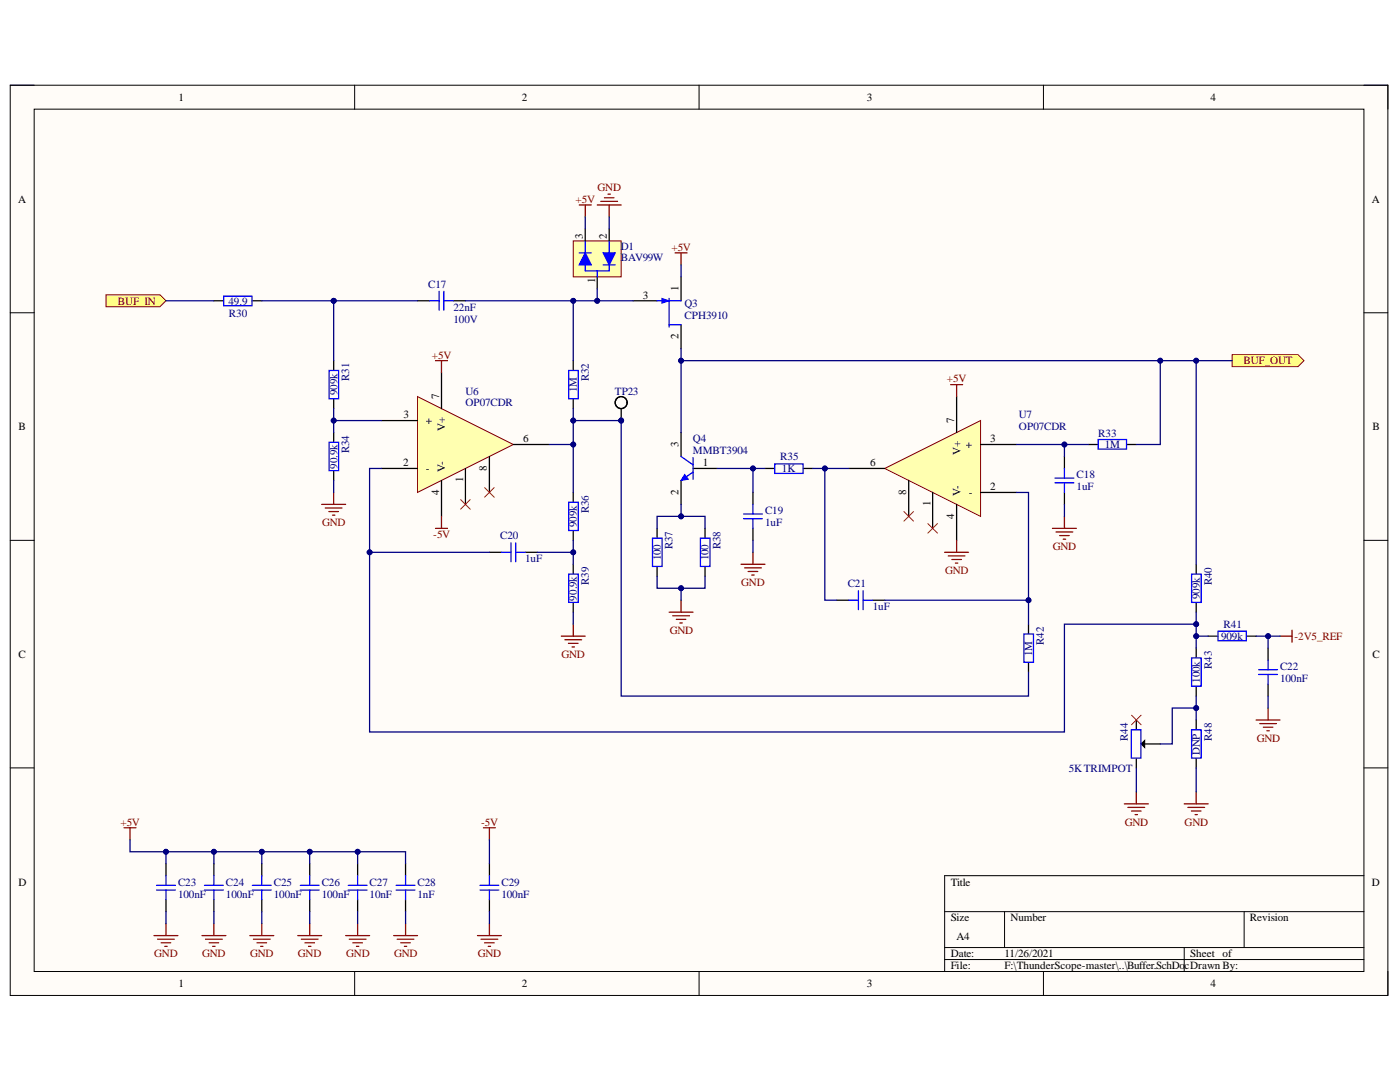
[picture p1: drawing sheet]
<svg xmlns="http://www.w3.org/2000/svg" width="279mm" height="216mm" viewBox="0 0 279 216" stroke-linecap="round" stroke-linejoin="round" font-family="sans-serif">
<defs><g id="words">
<g font-size="2.2">
<text x="35.6" y="20.1">1</text>
<text x="104.1" y="20.1">2</text>
<text x="173" y="20.1">3</text>
<text x="241.6" y="20.1">4</text>
<text x="3.6" y="40.4">A</text>
<text x="273.8" y="40.4">A</text>
<text x="116.3" y="47.6" transform="rotate(-90 116.3 47.6)">3</text>
<text x="121.1" y="47.6" transform="rotate(-90 121.1 47.6)">2</text>
<text x="118.8" y="56.5" transform="rotate(-90 118.8 56.5)">1</text>
<text x="128.3" y="59.6">3</text>
<text x="135.4" y="58.1" transform="rotate(-90 135.4 58.1)">1</text>
<text x="135.4" y="67.7" transform="rotate(-90 135.4 67.7)">2</text>
<text x="80.5" y="83.5">3</text>
<text x="87.6" y="79.6" transform="rotate(-90 87.6 79.6)">7</text>
<text x="3.7" y="85.8">B</text>
<text x="85" y="84.6">+</text>
<text x="88.8" y="85.9" transform="rotate(-90 88.8 85.9)">V+</text>
<text x="104.4" y="88.3">6</text>
<text x="135.4" y="89.1" transform="rotate(-90 135.4 89.1)">3</text>
<text x="190.4" y="84.4" transform="rotate(-90 190.4 84.4)">7</text>
<text x="192.8" y="89.5">+</text>
<text x="197.6" y="88.3">3</text>
<text x="273.9" y="85.8">B</text>
<text x="80.4" y="93">2</text>
<text x="85" y="94.2">-</text>
<text x="88.8" y="94.2" transform="rotate(-90 88.8 94.2)">V-</text>
<text x="97.2" y="94" transform="rotate(-90 97.2 94)">8</text>
<text x="140.2" y="93">1</text>
<text x="173.7" y="93">6</text>
<text x="191.7" y="90.7" transform="rotate(-90 191.7 90.7)">V+</text>
<text x="87.6" y="98.8" transform="rotate(-90 87.6 98.8)">4</text>
<text x="92.5" y="96.2" transform="rotate(-90 92.5 96.2)">1</text>
<text x="135.4" y="98.8" transform="rotate(-90 135.4 98.8)">2</text>
<text x="180.8" y="98.8" transform="rotate(-90 180.8 98.8)">8</text>
<text x="185.7" y="101" transform="rotate(-90 185.7 101)">1</text>
<text x="191.7" y="98.9" transform="rotate(-90 191.7 98.9)">V-</text>
<text x="193.4" y="99">-</text>
<text x="197.6" y="97.8">2</text>
<text x="190.4" y="103.6" transform="rotate(-90 190.4 103.6)">4</text>
<text x="3.7" y="131.3">C</text>
<text x="273.9" y="131.3">C</text>
<text x="3.7" y="176.7">D</text>
<text x="189.7" y="176.7">Title</text>
<text x="273.8" y="176.7">D</text>
<text x="189.7" y="183.8">Size</text>
<text x="201.7" y="183.8">Number</text>
<text x="249.4" y="183.8">Revision</text>
<text x="189.7" y="191">Date:</text>
<text x="190.9" y="187.5">A4</text>
<text x="200.5" y="191">11/26/2021</text>
<text x="237.5" y="191">Sheet of</text>
<text x="35.6" y="197">1</text>
<text x="104.1" y="197">2</text>
<text x="173" y="197">3</text>
<text x="189.7" y="193.4">File:</text>
<text x="200.5" y="193.4">F:\ThunderScope-master\..\Buffer.SchDo</text>
<text x="236.4" y="193.4">cDrawn By:</text>
<text x="241.6" y="197">4</text>
</g>
<g font-size="2.2" fill="#800000">
<text x="114.9" y="40.4">+5V</text>
<text x="119.3" y="38.1">GND</text>
<text x="134" y="50.1">+5V</text>
<text x="23.5" y="60.8">BUF_IN</text>
<text x="86.2" y="71.5">+5V</text>
<text x="189" y="76.3">+5V</text>
<text x="248.2" y="72.7">BUF_OUT</text>
<text x="64.3" y="105">GND</text>
<text x="86.4" y="107.4">-5V</text>
<text x="210.1" y="109.8">GND</text>
<text x="147.9" y="116.9">GND</text>
<text x="188.6" y="114.6">GND</text>
<text x="112.1" y="131.3">GND</text>
<text x="133.6" y="126.5">GND</text>
<text x="258.3" y="127.7">-2V5_REF</text>
<text x="250.8" y="148">GND</text>
<text x="24" y="164.7">+5V</text>
<text x="96" y="164.7">-5V</text>
<text x="224.5" y="164.7">GND</text>
<text x="236.4" y="164.7">GND</text>
<text x="30.8" y="191">GND</text>
<text x="40.3" y="191">GND</text>
<text x="49.9" y="191">GND</text>
<text x="59.5" y="191">GND</text>
<text x="69.1" y="191">GND</text>
<text x="78.7" y="191">GND</text>
<text x="95.3" y="191">GND</text>
</g>
<g font-size="2.2" fill="#000080">
<text x="123.9" y="49.8">D1</text>
<text x="123.9" y="52.2">BAV99W</text>
<text x="85.4" y="57.4">C17</text>
<text x="45.6" y="60.8">49.9</text>
<text x="45.7" y="63.2">R30</text>
<text x="90.5" y="64.4">100V</text>
<text x="90.5" y="62">22nF</text>
<text x="136.6" y="61.2">Q3</text>
<text x="136.6" y="63.7">CPH3910</text>
<text x="69.7" y="76" transform="rotate(-90 69.7 76)">R31</text>
<text x="117.5" y="76.1" transform="rotate(-90 117.5 76.1)">R32</text>
<text x="67.3" y="78.9" transform="rotate(-90 67.3 78.9)">909k</text>
<text x="92.9" y="78.7">U6</text>
<text x="92.9" y="81.1">OP07CDR</text>
<text x="115.1" y="78.2" transform="rotate(-90 115.1 78.2)">1M</text>
<text x="122.7" y="78.7">TP23</text>
<text x="203.3" y="83.5">U7</text>
<text x="138.3" y="88.3">Q4</text>
<text x="203.3" y="85.8">OP07CDR</text>
<text x="219.2" y="87.3">R33</text>
<text x="220.5" y="89.5">1M</text>
<text x="67.3" y="93.5" transform="rotate(-90 67.3 93.5)">90.9k</text>
<text x="69.7" y="90.5" transform="rotate(-90 69.7 90.5)">R34</text>
<text x="138.3" y="90.7">MMBT3904</text>
<text x="155.7" y="91.8">R35</text>
<text x="156.1" y="94.2">1K</text>
<text x="214.9" y="95.5">C18</text>
<text x="214.9" y="97.8">1uF</text>
<text x="99.8" y="107.6">C20</text>
<text x="115.1" y="105.2" transform="rotate(-90 115.1 105.2)">909k</text>
<text x="117.5" y="102.4" transform="rotate(-90 117.5 102.4)">R36</text>
<text x="152.7" y="102.6">C19</text>
<text x="152.7" y="105">1uF</text>
<text x="104.8" y="112.1">1uF</text>
<text x="131.9" y="111.8" transform="rotate(-90 131.9 111.8)">100</text>
<text x="134.2" y="109.6" transform="rotate(-90 134.2 109.6)">R37</text>
<text x="141.4" y="111.8" transform="rotate(-90 141.4 111.8)">100</text>
<text x="143.8" y="109.5" transform="rotate(-90 143.8 109.5)">R38</text>
<text x="115.1" y="119.8" transform="rotate(-90 115.1 119.8)">90.9k</text>
<text x="117.5" y="116.7" transform="rotate(-90 117.5 116.7)">R39</text>
<text x="169.2" y="117.2">C21</text>
<text x="239.5" y="119.6" transform="rotate(-90 239.5 119.6)">909k</text>
<text x="241.8" y="116.8" transform="rotate(-90 241.8 116.8)">R40</text>
<text x="174.2" y="121.7">1uF</text>
<text x="244.2" y="125.3">R41</text>
<text x="206" y="130.8" transform="rotate(-90 206 130.8)">1M</text>
<text x="208.3" y="128.7" transform="rotate(-90 208.3 128.7)">R42</text>
<text x="243.7" y="127.7">909k</text>
<text x="239.5" y="136.2" transform="rotate(-90 239.5 136.2)">100k</text>
<text x="241.8" y="133.4" transform="rotate(-90 241.8 133.4)">R43</text>
<text x="255.5" y="133.7">C22</text>
<text x="255.5" y="136.1">100nF</text>
<text x="225.1" y="147.8" transform="rotate(-90 225.1 147.8)">R44</text>
<text x="241.8" y="147.8" transform="rotate(-90 241.8 147.8)">R48</text>
<text x="213.3" y="154">5KTRIMPOT</text>
<text x="239.5" y="150.6" transform="rotate(-90 239.5 150.6)">DNP</text>
<text x="35.5" y="176.7">C23</text>
<text x="35.5" y="179.1">100nF</text>
<text x="45.1" y="176.7">C24</text>
<text x="45.1" y="179.1">100nF</text>
<text x="54.6" y="176.7">C25</text>
<text x="54.6" y="179.1">100nF</text>
<text x="64.2" y="176.7">C26</text>
<text x="64.2" y="179.1">100nF</text>
<text x="73.8" y="176.7">C27</text>
<text x="73.8" y="179.1">10nF</text>
<text x="83.3" y="176.7">C28</text>
<text x="83.3" y="179.1">1nF</text>
<text x="100.1" y="176.7">C29</text>
<text x="100.1" y="179.1">100nF</text>
</g>
</g></defs>
<path d="M2 17h275v181.6h-275z" fill-rule="evenodd" fill="#fffcf8"/>
<path d="M2 17h275v181.6h-275z" fill="none" stroke="#000" stroke-width=".2"/>
<path d="M6.8 21.8h265.4v172.1h-265.4z" fill-rule="evenodd" fill="#fffcf8"/>
<g fill="none" stroke="#000" stroke-width=".2">
<path d="M2 17h4.8M70.8 17v4.8M139.5 17v4.8M208.2 17v4.8M272.2 17h4.8v4.8M6.8 21.8h265.4v172.1h-265.4zM2 62.4h4.8M272.2 62.4h4.8M2 107.8h4.8M272.2 107.8h4.8M2 153.2h4.8M272.2 153.2h4.8"/>
<path d="M272.2 174.7h-83.7v19.2M70.8 193.9v4.7M139.5 193.9v4.7M188.5 181.9h83.7M188.5 189.1h83.7M188.5 191.5h83.7M200.5 181.9v7.2M208.2 193.9v4.7M236.3 189.1v4.8M248.3 181.9v7.2M277 193.9v4.7"/>
</g>
<path d="M66.6 98.3v2.3M64.2 100.6h4.8M64.9 101.4h3.4M65.6 102.1h1.9M66.4 102.8h.4" fill="none" stroke="#800000" stroke-width=".25"/>
<path d="M83.3 79.1l19.2 9.6-19.2 9.6z" fill="#ffffb0"/>
<path d="M83.3 79.1l19.2 9.6-19.2 9.6z" fill="none" stroke="#800000" stroke-width=".2"/>
<path d="M88.1 74.4v7.1M76.2 83.9h7.1M76.2 93.5h7.1M88.1 95.9v7.1M92.9 93.5v7.1M97.7 91.1v7.2M102.5 88.7h7.1" fill="none" stroke="#000" stroke-width=".25"/>
<path d="M86.9 72h2.4M88.1 72v2.4M86.9 105.4h2.4M88.1 103v2.4M112 126.9h4.8M112.7 127.7h3.4M113.4 128.4h2M114.2 129.1h.4M114.4 124.5v2.4" fill="none" stroke="#800000" stroke-width=".25"/>
<path d="M91.9 99.7l1.9 1.9M93.8 99.7l-1.9 1.9M96.7 97.3l1.9 1.9M98.6 97.3l-1.9 1.9" fill="none" stroke="#f00" stroke-width=".2"/>
<path d="M21.2 58.8h10.7l1.2 1.2-1.2 1.2h-10.7z" fill-rule="evenodd" fill="#ffff80"/>
<path d="M21.2 58.8h10.7l1.2 1.2-1.2 1.2h-10.7z" fill="none" stroke="#800000" stroke-width=".2"/>
<path d="M114.4 72v1.8M114.4 79.6v1.9M135.9 86.3v4.8M135.9 95.9v4.7M138.3 93.5h4.8M97.7 110.2h2.4M104.8 110.2h2.4" fill="none" stroke="#000" stroke-width=".25"/>
<path d="M113.5 73.9h1.9v5.7h-1.9zM135.9 91.1l2.4 1.7M138.3 94.2l-2.4 1.7M138.3 91.3v4.3M100.1 110.2h1.9M102 108.3v3.8M102.9 110.2h1.9M102.9 108.3v3.8" fill="none" stroke="#00f" stroke-width=".25"/>
<path d="M134.7 50.5h2.4M135.9 50.5v2.4" fill="none" stroke="#800000" stroke-width=".25"/>
<path d="M136.6 94.7l.8 .9-1.5 .3z" fill="#00f"/>
<path d="M136.6 94.7l.8 .9-1.5 .3z" fill="none" stroke="#00f" stroke-width=".2"/>
<path d="M131.1 105.4v1.9M131.1 113.1v1.9M140.7 105.4v1.9M140.7 113.1v1.9" fill="none" stroke="#000" stroke-width=".25"/>
<path d="M130.2 107.4h1.9v5.6h-1.9zM139.8 107.4h1.9v5.6h-1.9z" fill="none" stroke="#00f" stroke-width=".25"/>
<path d="M135.9 119.8v2.4M133.5 122.2h4.8M134.2 122.9h3.4M135 123.6h1.9M135.7 124.3h.5" fill="none" stroke="#800000" stroke-width=".25"/>
<path d="M176.6 93.5l19.1-9.6v19.1z" fill="#ffffb0"/>
<path d="M176.6 93.5l19.1-9.6v19.1z" fill="none" stroke="#800000" stroke-width=".2"/>
<path d="M190.9 79.1v7.2M169.4 93.5h7.2M181.4 95.9v7.1M186.1 98.3v7.1M195.7 88.7h7.2M195.7 98.3h7.2M217.2 88.7h1.9M224.9 88.7h1.9M190.9 100.7v7.1M205.3 124.5v1.9M205.3 132.2v1.9" fill="none" stroke="#000" stroke-width=".25"/>
<path d="M189.7 76.8h2.4M190.9 76.8v2.3M147.9 112.6h4.8M148.6 113.3h3.3M149.3 114h1.9M150 114.7h.5M150.3 110.2v2.4M210 105.4h4.8M210.8 106.1h3.3M211.5 106.9h1.9M212.2 107.6h.5M212.4 103v2.4" fill="none" stroke="#800000" stroke-width=".25"/>
<path d="M180.4 102.1l1.9 1.9M182.3 102.1l-1.9 1.9M185.2 104.5l1.9 1.9M187.1 104.5l-1.9 1.9" fill="none" stroke="#f00" stroke-width=".2"/>
<path d="M219.2 87.7h5.6v1.9h-5.6zM204.3 126.5h2v5.6h-2z" fill="none" stroke="#00f" stroke-width=".25"/>
<path d="M245.9 70.8h13.1l1.2 1.2-1.2 1.2h-13.1z" fill-rule="evenodd" fill="#ffff80"/>
<path d="M245.9 70.8h13.1l1.2 1.2-1.2 1.2h-13.1z" fill="none" stroke="#800000" stroke-width=".2"/>
<g fill="none" stroke="#000" stroke-width=".25">
<path d="M135.9 55.2v4.8M126.4 60h4.7M135.9 64.8v4.8M212.4 91.1v2.4M212.4 98.3v2.4M167 119.8h2.4M174.2 119.8h2.4M42.7 172.3v2.4M42.7 179.5v2.4M52.2 172.3v2.4M52.2 179.5v2.4M61.8 172.3v2.4"/>
<path d="M61.8 179.5v2.4M71.4 172.3v2.4M71.4 179.5v2.4M80.9 172.3v2.4M80.9 179.5v2.4M97.7 172.3v2.4M97.7 179.5v2.4"/>
</g>
<g fill="none" stroke="#00f" stroke-width=".25">
<path d="M133.5 59.5v5.8M131.1 60h2.4M210.5 96.3h3.8M210.5 95.4h3.8M212.4 93.5v1.9M212.4 96.3v2M169.4 119.8h1.9M171.3 117.9v3.7M172.3 117.9v3.7M172.3 119.8h1.9M40.8 176.7h3.8M40.8 177.6h3.8"/>
<path d="M42.7 174.7v2M42.7 177.6v1.9M50.4 176.7h3.7M50.4 177.6h3.7M52.2 174.7v2M52.2 177.6v1.9M59.9 176.7h3.8M59.9 177.6h3.8M61.8 174.7v2M61.8 177.6v1.9M69.5 176.7h3.8M69.5 177.6h3.8"/>
<path d="M71.4 174.7v2M71.4 177.6v1.9M79.1 176.7h3.7M79.1 177.6h3.7M80.9 174.7v2M80.9 177.6v1.9M95.8 176.7h3.8M95.8 177.6h3.8M97.7 174.7v2M97.7 177.6v1.9"/>
</g>
<g fill="none" stroke="#800000" stroke-width=".25">
<path d="M188.5 110.2h4.8M189.2 110.9h3.4M190 111.6h1.9M190.7 112.4h.5M190.9 107.8v2.4M24.8 165.2h2.3M25.9 165.2v2.4M96.5 165.2h2.4M97.7 165.2v2.4M40.3 186.7h4.8M41 187.4h3.4M41.7 188.1h1.9"/>
<path d="M42.4 188.8h.5M42.7 184.3v2.4M49.9 186.7h4.7M50.6 187.4h3.3M51.3 188.1h1.9M52 188.8h.5M52.2 184.3v2.4M59.4 186.7h4.8M60.1 187.4h3.4M60.8 188.1h2M61.6 188.8h.5M61.8 184.3v2.4"/>
<path d="M69 186.7h4.8M69.7 187.4h3.4M70.4 188.1h1.9M71.1 188.8h.5M71.4 184.3v2.4M78.5 186.7h4.8M79.3 187.4h3.3M80 188.1h1.9M80.7 188.8h.5M80.9 184.3v2.4M95.3 186.7h4.8M96 187.4h3.3"/>
<path d="M96.7 188.1h1.9M97.4 188.8h.5M97.7 184.3v2.4"/>
</g>
<path d="M132.1 59.5l1.4 .5-1.4 .5z" fill="#00f"/>
<path d="M132.1 59.5l1.4 .5-1.4 .5z" fill="none" stroke="#00f" stroke-width=".2"/>
<g fill="none" stroke="#00f" stroke-width=".25">
<path d="M87.6 58.1v3.8M88.6 58.1v3.8M65.7 73.9h1.9v5.7h-1.9zM85.7 60h1.9M88.6 60h1.9M133.5 64.8h2.4M133.5 60h2.4M65.7 88.3h1.9v5.6h-1.9zM154.6 92.6h5.7v1.9h-5.7zM113.5 100.2h1.9v5.7h-1.9zM113.5 114.6h1.9v5.6h-1.9zM148.4 103.5h3.8"/>
<path d="M148.4 102.6h3.8M150.3 100.6v2M150.3 103.5v1.9M237.8 114.6h1.9v5.6h-1.9zM237.8 131.3h1.9v5.6h-1.9zM243.1 125.9h5.6v2h-5.6z"/>
</g>
<g fill="none" stroke="#000" stroke-width=".25">
<path d="M66.6 72v1.8M66.6 79.6v1.9M83.3 60h2.4M90.5 60h2.4M66.6 86.3v1.9M66.6 94v1.9M114.4 98.3v1.8M150.3 98.3v2.3M152.7 93.5h1.8M160.3 93.5h1.9M114.4 105.9v1.9M114.4 112.6v1.9"/>
<path d="M150.3 105.4v2.4M238.7 112.6v1.9M114.4 120.3v1.9M238.7 120.3v1.9M238.7 129.3v1.9M238.7 137v1.9M241.1 126.9h1.9M248.8 126.9h1.9"/>
</g>
<path d="M255.5 126.9h2.4M257.9 125.7v2.4" fill="none" stroke="#800000" stroke-width=".25"/>
<path d="M114.4 48.1h9.6v7.1h-9.6z" fill-rule="evenodd" fill="#ffffb0"/>
<path d="M114.4 48.1h9.6v7.1h-9.6z" fill="none" stroke="#800000" stroke-width=".2"/>
<path d="M115.6 50.5h2.4" fill="none" stroke="#00f" stroke-width=".25"/>
<path d="M116.8 50.5l1.2 2.4h-2.4z" fill="#00f"/>
<path d="M116.8 50.5l1.2 2.4h-2.4zM120.4 52.9h2.4" fill="none" stroke="#00f" stroke-width=".25"/>
<path d="M120.4 50.5h2.4l-1.2 2.4z" fill="#00f"/>
<g fill="none" stroke="#00f" stroke-width=".25">
<path d="M44.6 59.1h5.7v1.9h-5.7zM116.8 52.9v1.1h4.8v-1.1M116.8 48.1v2.4M119.2 54v1.2M120.4 50.5h2.4l-1.2 2.4zM121.6 48.1v2.4M251.2 133.6h3.8M251.2 134.6h3.8M253.1 131.7v1.9M253.1 134.6v1.9M31.2 176.7h3.8M31.2 177.6h3.8"/>
<path d="M33.1 174.7v2M33.1 177.6v1.9"/>
</g>
<path d="M116.8 45.7v2.4M119.2 55.2v2.4M121.6 45.7v2.4M42.7 60h1.9M50.4 60h1.8M253.1 129.3v2.4M253.1 136.5v2.4M33.1 172.3v2.4M33.1 179.5v2.4" fill="none" stroke="#000" stroke-width=".25"/>
<g fill="none" stroke="#800000" stroke-width=".25">
<path d="M120.6 39.5h1.9M121.3 38.7h.5M115.6 40.9h2.4M116.8 40.9v2.4M119.2 40.9h4.8M119.9 40.2h3.4M121.6 40.9v2.4M250.7 143.7h4.8M251.4 144.4h3.3M252.1 145.1h1.9M252.8 145.8h.5M253.1 141.3v2.4"/>
<path d="M30.7 186.7h4.8M31.4 187.4h3.4M32.2 188.1h1.9M32.9 188.8h.5M33.1 184.3v2.4"/>
</g>
<circle cx="124" cy="83.9" r=".48" fill="#000080"/>
<circle cx="124" cy="83.9" r=".48" fill="none" stroke="#000080" stroke-width=".2"/>
<path d="M124 81.5v2.4" fill="none" stroke="#000" stroke-width=".25"/>
<circle cx="124" cy="83.9" r=".48" fill="#000080"/>
<circle cx="124" cy="83.9" r=".48" fill="none" stroke="#000080" stroke-width=".2"/>
<g fill="none" stroke="#000" stroke-width=".25">
<path d="M226.8 143.7v1.9M226.8 151.3v1.9M227.7 148.4h3.9M238.7 143.7v1.9M238.7 151.3v1.9"/>
<circle cx="124" cy="80.3" r="1.19"/>
</g>
<path d="M225.8 145.6h1.9v5.7h-1.9zM237.8 145.6h1.9v5.7h-1.9z" fill="none" stroke="#00f" stroke-width=".25"/>
<path d="M226.8 158v2.4M238.7 158v2.4M224.4 160.4h4.8M225.1 161.1h3.3M225.8 161.8h1.9M226.5 162.5h.5M236.3 160.4h4.8M237.1 161.1h3.3M237.8 161.8h1.9M238.5 162.5h.5" fill="none" stroke="#800000" stroke-width=".25"/>
<path d="M227.7 148.4l.7-.7v1.5z" fill="#000"/>
<path d="M227.7 148.4l.7-.7v1.5z" fill="none" stroke="#000" stroke-width=".2"/>
<path d="M225.8 142.7l1.9 1.9M227.7 142.7l-1.9 1.9" fill="none" stroke="#f00" stroke-width=".2"/>
<path d="M253.1 126.9v2.4" fill="none" stroke="#000080" stroke-width=".25"/>
<circle cx="253.1" cy="126.9" r=".48" fill="#000080"/>
<circle cx="253.1" cy="126.9" r=".48" fill="none" stroke="#000080" stroke-width=".2"/>
<path d="M25.9 167.6v2.4h16.8v2.3" fill="none" stroke="#000080" stroke-width=".25"/>
<circle cx="33.1" cy="170" r=".48" fill="#000080"/>
<circle cx="33.1" cy="170" r=".48" fill="none" stroke="#000080" stroke-width=".2"/>
<circle cx="42.7" cy="170" r=".48" fill="#000080"/>
<circle cx="42.7" cy="170" r=".48" fill="none" stroke="#000080" stroke-width=".2"/>
<path d="M33.1 60h9.6M52.2 60h14.4" fill="none" stroke="#000080" stroke-width=".25"/>
<circle cx="66.6" cy="60" r=".48" fill="#000080"/>
<circle cx="66.6" cy="60" r=".48" fill="none" stroke="#000080" stroke-width=".2"/>
<path d="M76.2 83.9h-9.6v2.4" fill="none" stroke="#000080" stroke-width=".25"/>
<circle cx="66.6" cy="83.9" r=".48" fill="#000080"/>
<circle cx="66.6" cy="83.9" r=".48" fill="none" stroke="#000080" stroke-width=".2"/>
<path d="M66.6 60h16.7" fill="none" stroke="#000080" stroke-width=".25"/>
<circle cx="66.6" cy="60" r=".48" fill="#000080"/>
<circle cx="66.6" cy="60" r=".48" fill="none" stroke="#000080" stroke-width=".2"/>
<path d="M73.8 110.2v35.9h138.6v-21.6h26.3" fill="none" stroke="#000080" stroke-width=".25"/>
<circle cx="238.7" cy="124.5" r=".48" fill="#000080"/>
<circle cx="238.7" cy="124.5" r=".48" fill="none" stroke="#000080" stroke-width=".2"/>
<circle cx="73.8" cy="110.2" r=".48" fill="#000080"/>
<circle cx="73.8" cy="110.2" r=".48" fill="none" stroke="#000080" stroke-width=".2"/>
<path d="M76.2 93.5h-2.4v16.7h23.9" fill="none" stroke="#000080" stroke-width=".25"/>
<circle cx="73.8" cy="110.2" r=".48" fill="#000080"/>
<circle cx="73.8" cy="110.2" r=".48" fill="none" stroke="#000080" stroke-width=".2"/>
<path d="M92.9 60h33.5" fill="none" stroke="#000080" stroke-width=".25"/>
<circle cx="114.4" cy="60" r=".48" fill="#000080"/>
<circle cx="114.4" cy="60" r=".48" fill="none" stroke="#000080" stroke-width=".2"/>
<circle cx="119.2" cy="60" r=".48" fill="#000080"/>
<circle cx="119.2" cy="60" r=".48" fill="none" stroke="#000080" stroke-width=".2"/>
<path d="M114.4 107.8v2.4h-7.2" fill="none" stroke="#000080" stroke-width=".25"/>
<circle cx="114.4" cy="110.2" r=".48" fill="#000080"/>
<circle cx="114.4" cy="110.2" r=".48" fill="none" stroke="#000080" stroke-width=".2"/>
<path d="M109.6 88.7h4.8v9.6" fill="none" stroke="#000080" stroke-width=".25"/>
<circle cx="114.4" cy="88.7" r=".48" fill="#000080"/>
<circle cx="114.4" cy="88.7" r=".48" fill="none" stroke="#000080" stroke-width=".2"/>
<path d="M114.4 83.9h9.6v55h81.3v-4.8" fill="none" stroke="#000080" stroke-width=".25"/>
<circle cx="124" cy="83.9" r=".48" fill="#000080"/>
<circle cx="124" cy="83.9" r=".48" fill="none" stroke="#000080" stroke-width=".2"/>
<circle cx="114.4" cy="83.9" r=".48" fill="#000080"/>
<circle cx="114.4" cy="83.9" r=".48" fill="none" stroke="#000080" stroke-width=".2"/>
<path d="M131.1 115v2.4h4.8v2.4" fill="none" stroke="#000080" stroke-width=".25"/>
<circle cx="135.9" cy="117.4" r=".48" fill="#000080"/>
<circle cx="135.9" cy="117.4" r=".48" fill="none" stroke="#000080" stroke-width=".2"/>
<path d="M135.9 100.6v2.4h-4.8v2.4" fill="none" stroke="#000080" stroke-width=".25"/>
<circle cx="135.9" cy="103" r=".48" fill="#000080"/>
<circle cx="135.9" cy="103" r=".48" fill="none" stroke="#000080" stroke-width=".2"/>
<path d="M140.7 115v2.4h-4.8" fill="none" stroke="#000080" stroke-width=".25"/>
<circle cx="135.9" cy="117.4" r=".48" fill="#000080"/>
<circle cx="135.9" cy="117.4" r=".48" fill="none" stroke="#000080" stroke-width=".2"/>
<path d="M135.9 103h4.8v2.4" fill="none" stroke="#000080" stroke-width=".25"/>
<circle cx="135.9" cy="103" r=".48" fill="#000080"/>
<circle cx="135.9" cy="103" r=".48" fill="none" stroke="#000080" stroke-width=".2"/>
<path d="M135.9 72h110" fill="none" stroke="#000080" stroke-width=".25"/>
<circle cx="135.9" cy="72" r=".48" fill="#000080"/>
<circle cx="135.9" cy="72" r=".48" fill="none" stroke="#000080" stroke-width=".2"/>
<circle cx="231.6" cy="72" r=".48" fill="#000080"/>
<circle cx="231.6" cy="72" r=".48" fill="none" stroke="#000080" stroke-width=".2"/>
<circle cx="238.7" cy="72" r=".48" fill="#000080"/>
<circle cx="238.7" cy="72" r=".48" fill="none" stroke="#000080" stroke-width=".2"/>
<path d="M143.1 93.5h7.2v4.8" fill="none" stroke="#000080" stroke-width=".25"/>
<circle cx="150.3" cy="93.5" r=".48" fill="#000080"/>
<circle cx="150.3" cy="93.5" r=".48" fill="none" stroke="#000080" stroke-width=".2"/>
<path d="M150.3 93.5h2.4" fill="none" stroke="#000080" stroke-width=".25"/>
<circle cx="150.3" cy="93.5" r=".48" fill="#000080"/>
<circle cx="150.3" cy="93.5" r=".48" fill="none" stroke="#000080" stroke-width=".2"/>
<path d="M162.2 93.5h7.2" fill="none" stroke="#000080" stroke-width=".25"/>
<circle cx="164.6" cy="93.5" r=".48" fill="#000080"/>
<circle cx="164.6" cy="93.5" r=".48" fill="none" stroke="#000080" stroke-width=".2"/>
<path d="M164.6 93.5v26.3h2.4" fill="none" stroke="#000080" stroke-width=".25"/>
<circle cx="164.6" cy="93.5" r=".48" fill="#000080"/>
<circle cx="164.6" cy="93.5" r=".48" fill="none" stroke="#000080" stroke-width=".2"/>
<path d="M176.6 119.8h28.7" fill="none" stroke="#000080" stroke-width=".25"/>
<circle cx="205.3" cy="119.8" r=".48" fill="#000080"/>
<circle cx="205.3" cy="119.8" r=".48" fill="none" stroke="#000080" stroke-width=".2"/>
<path d="M202.9 98.3h2.4v26.2" fill="none" stroke="#000080" stroke-width=".25"/>
<circle cx="205.3" cy="119.8" r=".48" fill="#000080"/>
<circle cx="205.3" cy="119.8" r=".48" fill="none" stroke="#000080" stroke-width=".2"/>
<path d="M202.9 88.7h9.5v2.4" fill="none" stroke="#000080" stroke-width=".25"/>
<circle cx="212.4" cy="88.7" r=".48" fill="#000080"/>
<circle cx="212.4" cy="88.7" r=".48" fill="none" stroke="#000080" stroke-width=".2"/>
<path d="M212.4 88.7h4.8" fill="none" stroke="#000080" stroke-width=".25"/>
<circle cx="212.4" cy="88.7" r=".48" fill="#000080"/>
<circle cx="212.4" cy="88.7" r=".48" fill="none" stroke="#000080" stroke-width=".2"/>
<path d="M231.6 72v16.7h-4.8" fill="none" stroke="#000080" stroke-width=".25"/>
<circle cx="231.6" cy="72" r=".48" fill="#000080"/>
<circle cx="231.6" cy="72" r=".48" fill="none" stroke="#000080" stroke-width=".2"/>
<path d="M238.7 126.9h2.4" fill="none" stroke="#000080" stroke-width=".25"/>
<circle cx="238.7" cy="126.9" r=".48" fill="#000080"/>
<circle cx="238.7" cy="126.9" r=".48" fill="none" stroke="#000080" stroke-width=".2"/>
<path d="M250.7 126.9h4.8" fill="none" stroke="#000080" stroke-width=".25"/>
<circle cx="253.1" cy="126.9" r=".48" fill="#000080"/>
<circle cx="253.1" cy="126.9" r=".48" fill="none" stroke="#000080" stroke-width=".2"/>
<path d="M33.1 170v2.3M33.1 181.9v2.4" fill="none" stroke="#000080" stroke-width=".25"/>
<circle cx="33.1" cy="170" r=".48" fill="#000080"/>
<circle cx="33.1" cy="170" r=".48" fill="none" stroke="#000080" stroke-width=".2"/>
<path d="M52.2 170v2.3M42.7 181.9v2.4M52.2 181.9v2.4" fill="none" stroke="#000080" stroke-width=".25"/>
<circle cx="52.2" cy="170" r=".48" fill="#000080"/>
<circle cx="52.2" cy="170" r=".48" fill="none" stroke="#000080" stroke-width=".2"/>
<path d="M61.8 170v2.3M61.8 181.9v2.4" fill="none" stroke="#000080" stroke-width=".25"/>
<circle cx="61.8" cy="170" r=".48" fill="#000080"/>
<circle cx="61.8" cy="170" r=".48" fill="none" stroke="#000080" stroke-width=".2"/>
<path d="M66.6 81.5v2.4M66.6 95.9v2.4" fill="none" stroke="#000080" stroke-width=".25"/>
<circle cx="66.6" cy="83.9" r=".48" fill="#000080"/>
<circle cx="66.6" cy="83.9" r=".48" fill="none" stroke="#000080" stroke-width=".2"/>
<path d="M66.6 60v12" fill="none" stroke="#000080" stroke-width=".25"/>
<circle cx="66.6" cy="60" r=".48" fill="#000080"/>
<circle cx="66.6" cy="60" r=".48" fill="none" stroke="#000080" stroke-width=".2"/>
<path d="M71.4 170v2.3M71.4 181.9v2.4" fill="none" stroke="#000080" stroke-width=".25"/>
<circle cx="71.4" cy="170" r=".48" fill="#000080"/>
<circle cx="71.4" cy="170" r=".48" fill="none" stroke="#000080" stroke-width=".2"/>
<path d="M114.4 110.2v2.4M114.4 122.2v2.3M97.7 167.6v4.7M80.9 181.9v2.4M97.7 181.9v2.4" fill="none" stroke="#000080" stroke-width=".25"/>
<circle cx="114.4" cy="110.2" r=".48" fill="#000080"/>
<circle cx="114.4" cy="110.2" r=".48" fill="none" stroke="#000080" stroke-width=".2"/>
<path d="M114.4 81.5v7.2" fill="none" stroke="#000080" stroke-width=".25"/>
<circle cx="114.4" cy="83.9" r=".48" fill="#000080"/>
<circle cx="114.4" cy="83.9" r=".48" fill="none" stroke="#000080" stroke-width=".2"/>
<circle cx="114.4" cy="88.7" r=".48" fill="#000080"/>
<circle cx="114.4" cy="88.7" r=".48" fill="none" stroke="#000080" stroke-width=".2"/>
<path d="M114.4 60v12" fill="none" stroke="#000080" stroke-width=".25"/>
<circle cx="114.4" cy="60" r=".48" fill="#000080"/>
<circle cx="114.4" cy="60" r=".48" fill="none" stroke="#000080" stroke-width=".2"/>
<path d="M116.8 43.3v2.4M119.2 57.6v2.4" fill="none" stroke="#000080" stroke-width=".25"/>
<circle cx="119.2" cy="60" r=".48" fill="#000080"/>
<circle cx="119.2" cy="60" r=".48" fill="none" stroke="#000080" stroke-width=".2"/>
<path d="M121.6 43.3v2.4M135.9 69.6v16.7" fill="none" stroke="#000080" stroke-width=".25"/>
<circle cx="135.9" cy="72" r=".48" fill="#000080"/>
<circle cx="135.9" cy="72" r=".48" fill="none" stroke="#000080" stroke-width=".2"/>
<path d="M135.9 52.9v2.3M238.7 72v40.6M150.3 107.8v2.4M212.4 100.7v2.3" fill="none" stroke="#000080" stroke-width=".25"/>
<circle cx="238.7" cy="72" r=".48" fill="#000080"/>
<circle cx="238.7" cy="72" r=".48" fill="none" stroke="#000080" stroke-width=".2"/>
<path d="M253.1 138.9v2.4M42.7 170h38.2v2.3" fill="none" stroke="#000080" stroke-width=".25"/>
<circle cx="42.7" cy="170" r=".48" fill="#000080"/>
<circle cx="42.7" cy="170" r=".48" fill="none" stroke="#000080" stroke-width=".2"/>
<circle cx="52.2" cy="170" r=".48" fill="#000080"/>
<circle cx="52.2" cy="170" r=".48" fill="none" stroke="#000080" stroke-width=".2"/>
<circle cx="61.8" cy="170" r=".48" fill="#000080"/>
<circle cx="61.8" cy="170" r=".48" fill="none" stroke="#000080" stroke-width=".2"/>
<circle cx="71.4" cy="170" r=".48" fill="#000080"/>
<circle cx="71.4" cy="170" r=".48" fill="none" stroke="#000080" stroke-width=".2"/>
<path d="M238.7 138.9v4.8M226.8 153.2v4.8M238.7 153.2v4.8" fill="none" stroke="#000080" stroke-width=".25"/>
<circle cx="238.7" cy="141.3" r=".48" fill="#000080"/>
<circle cx="238.7" cy="141.3" r=".48" fill="none" stroke="#000080" stroke-width=".2"/>
<path d="M238.7 122.2v7.1" fill="none" stroke="#000080" stroke-width=".25"/>
<circle cx="238.7" cy="124.5" r=".48" fill="#000080"/>
<circle cx="238.7" cy="124.5" r=".48" fill="none" stroke="#000080" stroke-width=".2"/>
<circle cx="238.7" cy="126.9" r=".48" fill="#000080"/>
<circle cx="238.7" cy="126.9" r=".48" fill="none" stroke="#000080" stroke-width=".2"/>
<path d="M238.7 141.3h-4.8v7.1h-2.3" fill="none" stroke="#000080" stroke-width=".25"/>
<circle cx="238.7" cy="141.3" r=".48" fill="#000080"/>
<circle cx="238.7" cy="141.3" r=".48" fill="none" stroke="#000080" stroke-width=".2"/>
<use href="#words"/>
</svg>
